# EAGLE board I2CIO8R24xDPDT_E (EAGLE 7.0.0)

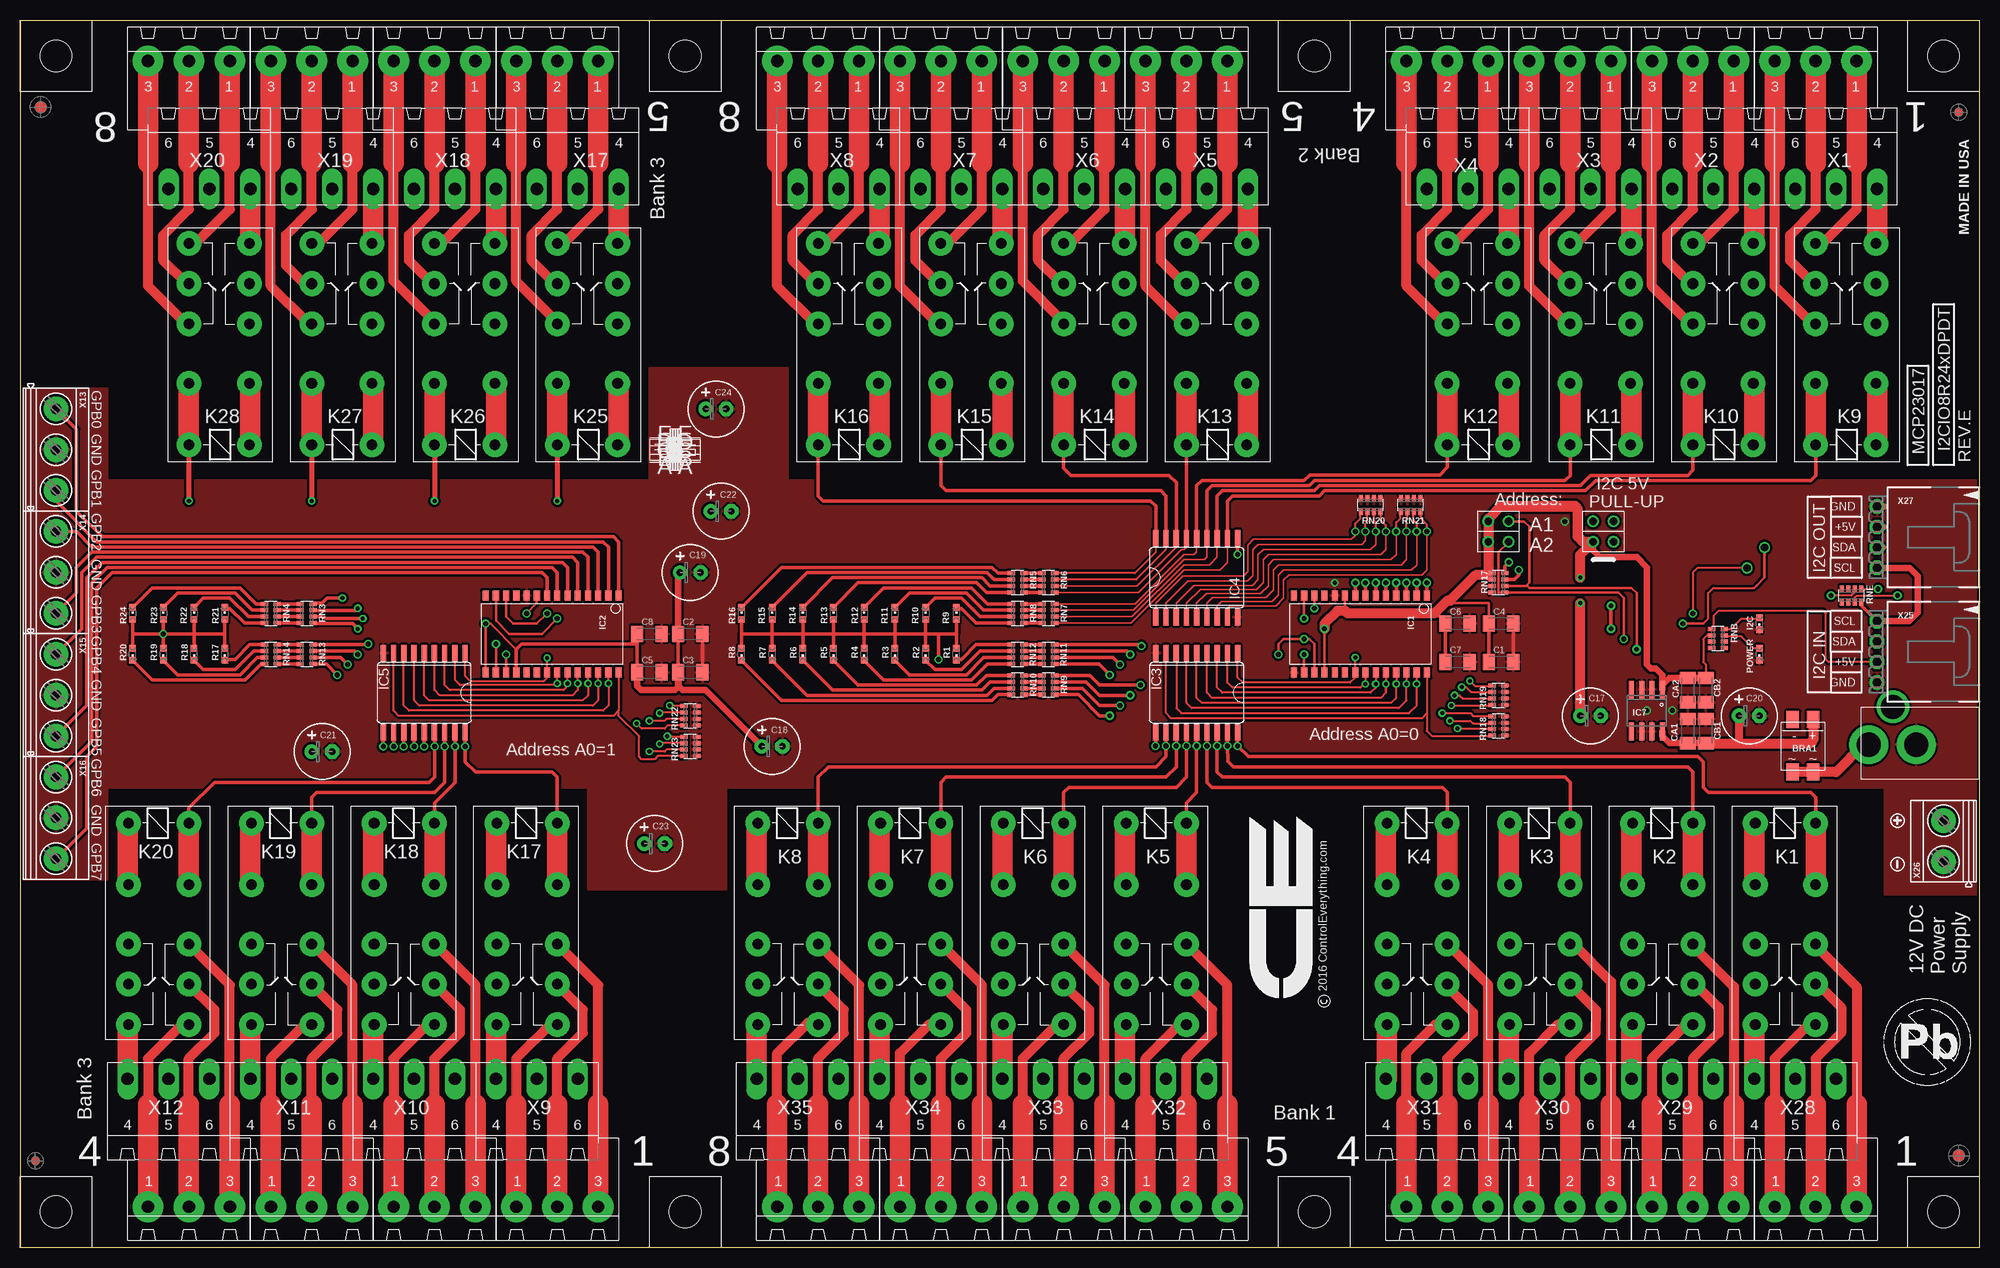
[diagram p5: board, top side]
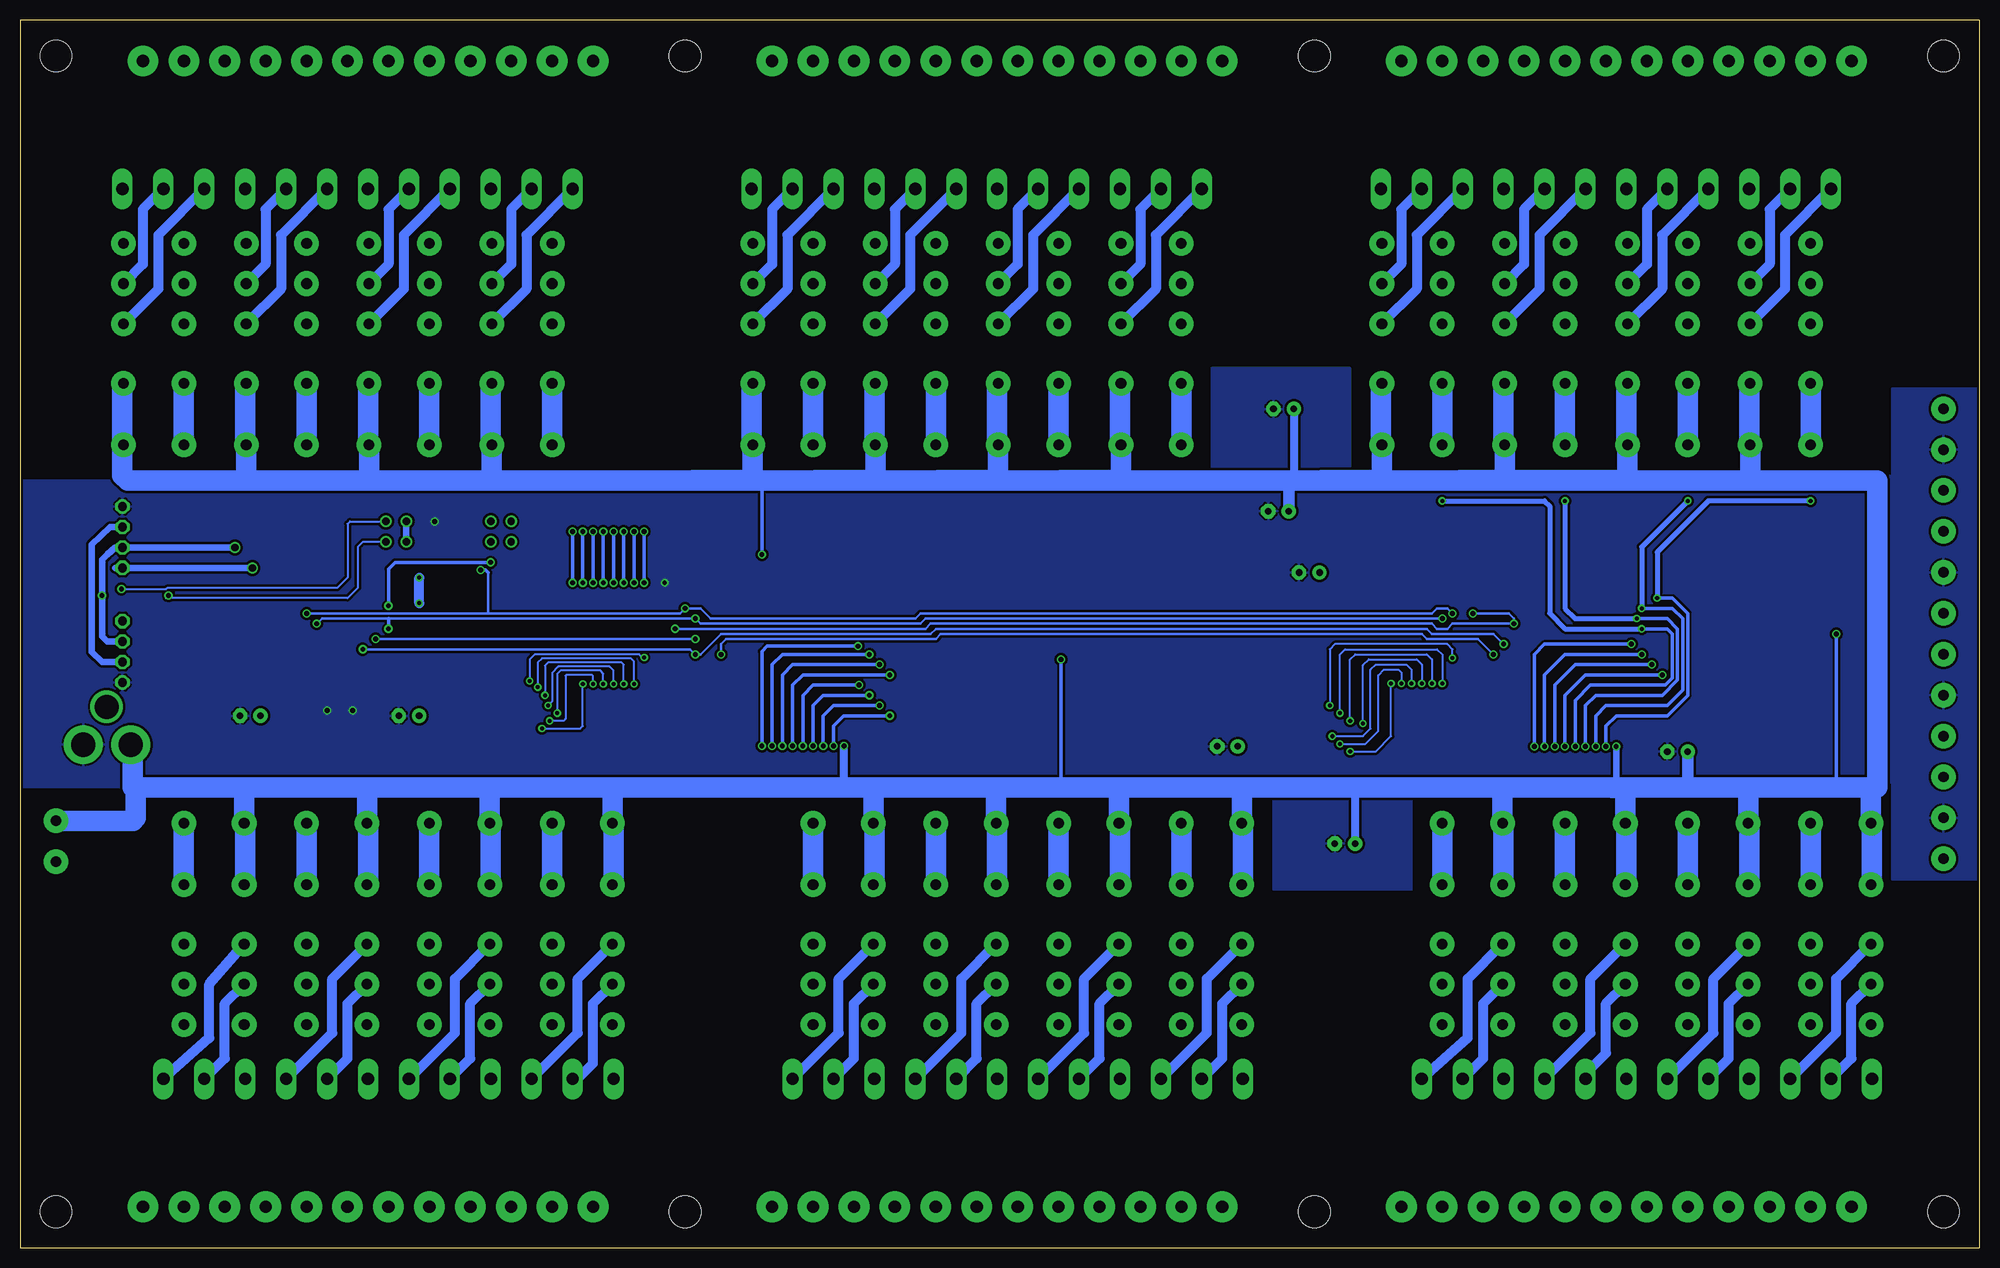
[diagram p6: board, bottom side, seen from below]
Size 243.2 x 152.41 mm. Coordinates in mm from the lower left corner, seen from the top.
Outline: 243.19,0 243.19,152.41 0,152.41 0,0.01 243.2,0.01
Copper layers (1*16): Top 0.035mm / dielectric 1.5mm / Bottom 0.035mm
Design rules "default": minimum track width 5mil, minimum drill 24mil, track to track 5mil, track to pad 5mil, pad to pad 5mil, via to via 5mil, smd to smd 5mil, copper to edge 10mil, drill to drill 8mil, minimum pad ring 10mil, minimum via ring 8mil, stop-mask expansion 2mil, vias tented up to drill 0mil, thermal gap 10mil

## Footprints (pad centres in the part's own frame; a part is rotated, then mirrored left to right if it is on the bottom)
MB2S = smd 1.55 x 2.1: + 0,-6.5; - 2.54,-6.5; ~@1 0,0; ~@2 2.54,0
_CA_.1UF_50V = smd 1.5 x 2: 1 -1.5,0; 2 1.5,0
_CB_10UF_25V = smd 1.5 x 2: 1 -1.5,0; 2 1.5,0
E-025X060 = drill 0.813 pad 1.778: + -1.27,0 | drill 0.813 pad 1.778 octagon: - 1.27,0
CC1206KRX7R9BB104 = smd 1.5 x 2: 1 -1.5,0; 2 1.5,0
TMK316F106ZL-T = smd 1.5 x 2: 1 -1.5,0; 2 1.5,0
CHIPLED_0603 = smd 0.8 x 0.8: A 0,-0.75; C 0,0.75
SO28W = smd 0.762 x 1.27: 1 -7.62,-4.78; 2 -6.35,-4.78; 3 -5.08,-4.78; 4 -3.81,-4.78; 5 -2.54,-4.78; 6 -1.27,-4.78; 7 0,-4.78; 8 1.27,-4.78; 9 2.54,-4.78; 10 3.81,-4.78; 11 5.08,-4.78; 12 6.35,-4.78; 13 7.62,-4.78; 14 8.89,-4.78; 15 8.89,4.78; 16 7.62,4.78; 17 6.35,4.78; 18 5.08,4.78; 19 3.81,4.78; 20 2.54,4.78; 21 1.27,4.78; 22 0,4.78; 23 -1.27,4.78; 24 -2.54,4.78; 25 -3.81,4.78; 26 -5.08,4.78; 27 -6.35,4.78; 28 -7.62,4.78
SO18L = smd 0.66 x 2.032: 1 -5.08,-4.902; 2 -3.81,-4.902; 3 -2.54,-4.902; 4 -1.27,-4.902; 5 0,-4.902; 6 1.27,-4.902; 7 2.54,-4.902; 8 3.81,-4.902; 9 5.08,-4.902; 10 5.08,4.902; 11 3.81,4.902; 12 2.54,4.902; 13 1.27,4.902; 14 0,4.902; 15 -1.27,4.902; 16 -2.54,4.902; 17 -3.81,4.902; 18 -5.08,4.902
_RGC_5V_SOIC8 = smd 0.6 x 2.2: 1 -1.905,-2.6; 2 -0.635,-2.6; 3 0.635,-2.6; 4 1.905,-2.6; 5 1.905,2.6; 6 0.635,2.6; 7 -0.635,2.6; 8 -1.905,2.6
G2R2 = drill 1.321 pad 3.048: 1 -2.54,-3.683; 2 -2.54,3.81; 3 5.08,-3.683; 4 5.08,3.81; O1 12.471,3.81; O2 12.471,-3.683; P1 17.45,3.81; P2 17.45,-3.683; S1 22.454,3.81; S2 22.454,-3.683
RNB = smd 0.5 x 0.9: 1 -1.2,-0.8; 2 -0.4,-0.8; 3 0.4,-0.8; 4 1.2,-0.8; 5 1.2,0.8; 6 0.4,0.8; 7 -0.4,0.8; 8 -1.2,0.8
RNE = smd 0.5 x 0.9: 1 -1.2,-0.8; 2 -0.4,-0.8; 3 0.4,-0.8; 4 1.2,-0.8; 5 1.2,0.8; 6 0.4,0.8; 7 -0.4,0.8; 8 -1.2,0.8
RND = smd 0.5 x 0.9: 1 -1.2,-0.8; 2 -0.4,-0.8; 3 0.4,-0.8; 4 1.2,-0.8; 5 1.2,0.8; 6 0.4,0.8; 7 -0.4,0.8; 8 -1.2,0.8
PCB_MOUNTING_HOLE = hole 3.962: 4.445,4.445
JUMPER_2X2 = drill 0.9: A1 0,2.54; A2 0,0; B1 2.54,2.54; B2 2.54,0
PJ-102A = drill 3 pad 4.8: RING 0.1,-3.39; TIP 0.1,-9.29 | drill 3 pad 3.251: RING_SW -4.6,-6.29
MDSTB3 = drill 1.524 pad 3.81: 1 -3.81,-10.795; 2 1.27,-10.795; 3 6.35,-10.795 | drill 1.524 pad 2.54 long: 4 -6.35,5.08; 5 -1.27,5.08; 6 3.81,5.08
MKDSN1,5/3-5,08 = drill 1.3 pad 3.048: 1 -7.641,0.025; 2 -2.561,0.025; 3 2.519,0.025
15-91-04 = drill 1.1 pad 1.778 octagon: 1 -3.81,-7.62; 2 -1.27,-7.62; 3 1.27,-7.62; 4 3.81,-7.62
MKDSN1,5/2-5,08 = drill 1.3 pad 3.048: 1 -2.561,0.025; 2 2.519,0.025

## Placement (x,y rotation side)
BRA1  MB2S_  [MB2S]  222.57,59.07 180 top
C1  [_CA_.1UF_50V]  183.83,72.72 0 top
C2  _CB_10UF_25VC1206K  [_CB_10UF_25V]  83.18,76.21 0 top
C3  [_CA_.1UF_50V]  83.18,71.45 0 top
C4  _CB_10UF_25VC1206K  [_CB_10UF_25V]  183.83,77.48 0 top
C5  [_CA_.1UF_50V]  78.11,71.45 0 top
C6  _CB_10UF_25VC1206K  [_CB_10UF_25V]  178.44,77.48 0 top
C7  [_CA_.1UF_50V]  178.44,72.72 0 top
C8  _CB_10UF_25VC1206K  [_CB_10UF_25V]  78.11,76.21 0 top
C17  100uF  [E-025X060]  194.94,66.05 0 top
C18  100uF  [E-025X060]  93.34,62.24 0 top
C19  100uF  [E-025X060]  83.18,83.83 0 top
C20  100uF  [E-025X060]  214.63,66.05 0 top
C21  100uF  [E-025X060]  37.46,61.61 0 top
C22  100uF  [E-025X060]  86.99,91.45 0 top
C23  100uF  [E-025X060]  78.74,50.18 0 top
C24  100uF  [E-025X060]  86.36,104.15 0 top
CA1  [CC1206KRX7R9BB104]  207.01,64.15 270 top
CA2  [CC1206KRX7R9BB104]  207.01,69.23 90 top
CB1  [TMK316F106ZL-T]  209.23,64.15 270 top
CB2  [TMK316F106ZL-T]  209.23,69.23 90 top
I2C  LED_NCD  [CHIPLED_0603]  215.9,77.48 180 top
IC1  MCP23017SO  [SO28W]  167,76.21 180 top
IC2  MCP23017SO  [SO28W]  66.67,76.21 180 top
IC3  ULN2803  [SO18L]  146.05,68.91 180 top
IC4  ULN2803  [SO18L]  146.05,83.2 0 top
IC5  ULN2803  [SO18L]  50.17,68.91 180 top
IC7  _RGC_5V_SOIC805  [_RGC_5V_SOIC8]  201.93,66.69 180 top
K1  G2R2  [G2R2]  219.07,50.18 270 top
K2  G2R2  [G2R2]  203.83,50.18 270 top
K3  G2R2  [G2R2]  188.59,50.18 270 top
K4  G2R2  [G2R2]  173.36,50.18 270 top
K5  G2R2  [G2R2]  140.97,50.18 270 top
K6  G2R2  [G2R2]  125.73,50.18 270 top
K7  G2R2  [G2R2]  110.49,50.18 270 top
K8  G2R2  [G2R2]  95.25,50.18 270 top
K9  G2R2  [G2R2]  226.69,102.25 90 top
K10  G2R2  [G2R2]  211.45,102.25 90 top
K11  G2R2  [G2R2]  196.21,102.25 90 top
K12  G2R2  [G2R2]  180.97,102.25 90 top
K13  G2R2  [G2R2]  148.59,102.25 90 top
K14  G2R2  [G2R2]  133.35,102.25 90 top
K15  G2R2  [G2R2]  118.11,102.25 90 top
K16  G2R2  [G2R2]  102.87,102.25 90 top
K17  G2R2  [G2R2]  62.86,50.18 270 top
K18  G2R2  [G2R2]  47.62,50.18 270 top
K19  G2R2  [G2R2]  32.38,50.18 270 top
K20  G2R2  [G2R2]  17.14,50.18 270 top
K25  G2R2  [G2R2]  70.48,102.25 90 top
K26  G2R2  [G2R2]  55.24,102.25 90 top
K27  G2R2  [G2R2]  40,102.25 90 top
K28  G2R2  [G2R2]  24.77,102.25 90 top
POWER  LED_NCD  [CHIPLED_0603]  215.9,73.67 180 top
R1  LED_NCD  [CHIPLED_0603]  116.2,73.67 180 top
R2  LED_NCD  [CHIPLED_0603]  112.39,73.67 180 top
R3  LED_NCD  [CHIPLED_0603]  108.58,73.67 180 top
R4  LED_NCD  [CHIPLED_0603]  104.77,73.67 180 top
R5  LED_NCD  [CHIPLED_0603]  100.96,73.67 180 top
R6  LED_NCD  [CHIPLED_0603]  97.15,73.67 180 top
R7  LED_NCD  [CHIPLED_0603]  93.34,73.67 180 top
R8  LED_NCD  [CHIPLED_0603]  89.53,73.67 180 top
R9  LED_NCD  [CHIPLED_0603]  116.2,78.75 0 top
R10  LED_NCD  [CHIPLED_0603]  112.39,78.75 0 top
R11  LED_NCD  [CHIPLED_0603]  108.58,78.75 0 top
R12  LED_NCD  [CHIPLED_0603]  104.77,78.75 0 top
R13  LED_NCD  [CHIPLED_0603]  100.96,78.75 0 top
R14  LED_NCD  [CHIPLED_0603]  97.15,78.75 0 top
R15  LED_NCD  [CHIPLED_0603]  93.34,78.75 0 top
R16  LED_NCD  [CHIPLED_0603]  89.53,78.75 0 top
R17  LED_NCD  [CHIPLED_0603]  25.4,73.67 180 top
R18  LED_NCD  [CHIPLED_0603]  21.59,73.67 180 top
R19  LED_NCD  [CHIPLED_0603]  17.78,73.67 180 top
R20  LED_NCD  [CHIPLED_0603]  13.97,73.67 180 top
R21  LED_NCD  [CHIPLED_0603]  25.4,78.75 0 top
R22  LED_NCD  [CHIPLED_0603]  21.59,78.75 0 top
R23  LED_NCD  [CHIPLED_0603]  17.78,78.75 0 top
R24  LED_NCD  [CHIPLED_0603]  13.97,78.75 0 top
RN3  _RNB_510  [RNB]  35.56,78.75 270 top
RN4  _RNB_510  [RNB]  31.11,78.75 270 top
RN5  _RNB_510  [RNB]  123.83,82.56 270 top
RN6  _RNB_510  [RNB]  127.64,82.56 270 top
RN7  _RNB_510  [RNB]  127.64,78.75 270 top
RN8  _RNB_510  [RNB]  123.83,78.75 270 top
RN9  _RNB_510  [RNB]  127.64,69.86 270 top
RN10  _RNB_510  [RNB]  123.83,69.86 270 top
RN11  _RNB_510  [RNB]  127.64,73.67 90 top
RN12  _RNB_510  [RNB]  123.83,73.67 90 top
RN13  _RNB_510  [RNB]  35.56,73.67 270 top
RN14  _RNB_510  [RNB]  31.11,73.67 270 top
RN17  _RNE_10K  [RNE]  183.51,82.56 270 top
RN18  _RNE_10K  [RNE]  183.51,64.78 90 top
RN19  _RNE_10K  [RNE]  183.51,68.59 90 top
RN20  _RNE_10K  [RNE]  167.64,92.21 180 top
RN21  _RNE_10K  [RNE]  172.59,92.21 180 top
RN22  _RNE_10K  [RNE]  83.18,66.05 90 top
RN23  _RNE_10K  [RNE]  83.18,62.24 90 top
RNB  _RNB_510  [RNB]  210.76,75.64 90 top
RNE  _RND_4.7K  [RND]  227.33,80.98 0 top
U$1  PCB_MOUNTING_HOLE  [PCB_MOUNTING_HOLE]  165.1,143.52 90 top
U$3  NOPB_LOGO_SYM  [NOPB_LOGO_SYM]  231.14,19.7 0 top
U$4  PCB_MOUNTING_HOLE  [PCB_MOUNTING_HOLE]  0,8.9 270 top
U$5  PCB_MOUNTING_HOLE  [PCB_MOUNTING_HOLE]  243.2,143.52 90 top
U$7  PCB_MOUNTING_HOLE  [PCB_MOUNTING_HOLE]  8.89,143.52 90 top
U$9  PCB_MOUNTING_HOLE  [PCB_MOUNTING_HOLE]  86.99,143.52 90 top
U$10  PCB_MOUNTING_HOLE  [PCB_MOUNTING_HOLE]  156.21,8.9 270 top
U$11  PCB_MOUNTING_HOLE  [PCB_MOUNTING_HOLE]  234.31,8.9 270 top
U$12  PCB_MOUNTING_HOLE  [PCB_MOUNTING_HOLE]  78.11,8.9 270 top
U$13  JUMPER_2X2  [JUMPER_2X2]  182.25,90.18 270 top
U$14  2.1MMJACK  [PJ-102A]  238.76,62.56 270 top
U$15  [VISION_REF15]  240.66,11.44 90 top
U$16  JUMPER_2X2  [JUMPER_2X2]  195.26,90.18 270 top
U$18  [VISION_REF10]  240.66,140.98 90 top
U$21  [ICON_USA]  241.94,125.74 90 top
U$22  [ICON_MINUS]  233.04,47.64 90 top
U$23  [VISION_REF15]  2.54,141.62 90 top
U$24  [ICON_PLUS]  233.04,53.04 0 top
U$28  [VISION_REF10]  1.91,10.81 90 top
X1  MDSTB3  [MDSTB3]  224.15,136.54 180 top
X2  MDSTB3  [MDSTB3]  208.91,136.54 180 top
X3  MDSTB3  [MDSTB3]  193.67,136.54 180 top
X4  MDSTB3  [MDSTB3]  178.44,136.54 180 top
X5  MDSTB3  [MDSTB3]  146.05,136.54 180 top
X6  MDSTB3  [MDSTB3]  130.81,136.54 180 top
X7  MDSTB3  [MDSTB3]  115.57,136.54 180 top
X8  MDSTB3  [MDSTB3]  100.33,136.54 180 top
X9  MDSTB3  [MDSTB3]  65.4,15.89 0 top
X10  MDSTB3  [MDSTB3]  50.17,15.89 0 top
X11  MDSTB3  [MDSTB3]  34.92,15.89 0 top
X12  MDSTB3  [MDSTB3]  19.69,15.89 0 top
X13  MKDSN1,5/3-5,08  [MKDSN1,5/3-5,08]  4.44,96.53 270 top
X14  MKDSN1,5/3-5,08  [MKDSN1,5/3-5,08]  4.44,81.29 270 top
X15  MKDSN1,5/3-5,08  [MKDSN1,5/3-5,08]  4.44,66.05 270 top
X16  MKDSN1,5/3-5,08  [MKDSN1,5/3-5,08]  4.44,50.81 270 top
X17  MDSTB3  [MDSTB3]  67.95,136.54 180 top
X18  MDSTB3  [MDSTB3]  52.7,136.54 180 top
X19  MDSTB3  [MDSTB3]  37.46,136.54 180 top
X20  MDSTB3  [MDSTB3]  22.22,136.54 180 top
X25  C-GRID-04-15-91-3044  [15-91-04]  238.12,73.99 270 top
X26  MKDSN1,5/2-5,08  [MKDSN1,5/2-5,08]  238.76,50.5 90 top
X27  C-GRID-04-15-91-3044  [15-91-04]  238.12,88.21 270 top
X28  MDSTB3  [MDSTB3]  221.62,15.89 0 top
X29  MDSTB3  [MDSTB3]  206.38,15.89 0 top
X30  MDSTB3  [MDSTB3]  191.13,15.89 0 top
X31  MDSTB3  [MDSTB3]  175.89,15.89 0 top
X32  MDSTB3  [MDSTB3]  143.51,15.89 0 top
X33  MDSTB3  [MDSTB3]  128.27,15.89 0 top
X34  MDSTB3  [MDSTB3]  113.03,15.89 0 top
X35  MDSTB3  [MDSTB3]  97.79,15.89 0 top

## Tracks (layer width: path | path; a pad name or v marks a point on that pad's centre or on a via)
GND  (via drill 0.5, 0.6)
  Top 0.406: C1.2 C4.2 | C3.2 C2.2 | 231.14,70.18 X25.4
  Top 0.813: X27.1 231.39,92.02
  other vias: 205.1,66.69 201.93,66.69 191.77,90.18 163.19,82.56
  pour Top (isolate 0.305): 243.14,43.83 231.46,43.83 231.46,57.16 243.14,57.16
  pour Top (isolate 0.305): 0,95.26 243.2,95.26 243.2,57.16 0,57.16
  pour Bottom (isolate 0.305): 0,57.8 0,95.9 243.2,95.26 243.2,57.16
  pour Bottom (isolate 0.305): 10.8,45.73 0,45.73 0,106.69 10.8,106.69
  pour Top (isolate 0.305): 10.8,45.73 0,45.73 0,106.69 10.8,106.69
  pour Top (isolate 0.305): 70.48,57.8 70.48,44.46 87.63,44.46 87.63,57.16 73.02,57.16 73.02,57.8
  pour Bottom (isolate 0.305): 70.48,44.46 70.48,57.8 87.63,57.8 87.63,44.46
  pour Bottom (isolate 0.305): 78.11,93.99 78.11,109.23 95.25,109.23 95.25,93.99
  pour Top (isolate 0.305): 78.11,94.63 78.11,109.23 95.25,109.23 95.25,94.63
GPB0
  Top 0.406: IC2.1 74.3,87.64 73.66,88.28 10.16,88.28 6.98,91.45 6.98,101.66 X13.1
GPB1
  Top 0.406: X13.3 4.42,92.74 9.52,87.64 72.39,87.64 73.02,87.01 IC2.2
GPB2
  Top 0.406: X14.1 7.01,88.93 8.89,87.01 71.12,87.01 71.76,86.37 IC2.3
GPB3
  Top 0.406: X14.3 6.98,81.29 6.98,84.47 8.89,86.37 69.85,86.37 70.48,85.74 IC2.4
GPB4
  Top 0.406: X15.1 7.62,76.85 7.62,83.83 9.52,85.74 68.58,85.74 69.21,85.1 IC2.5
GPB5
  Top 0.406: X15.3 8.25,67.32 8.25,83.2 10.16,85.1 67.31,85.1 67.95,84.47 IC2.6
GPB6
  Top 0.406: X16.1 8.89,62.88 8.89,82.56 10.8,84.47 66.04,84.47 66.67,83.83 IC2.7
GPB7
  Top 0.406: X16.3 8.25,52.08 8.25,60.97 9.52,62.24 9.52,81.93 11.43,83.83 64.77,83.83 65.4,83.2 IC2.8
I2C_SCL  (via drill 0.6, 0.9)
  Top 0.254: v214.38,84.4 208.22,84.4 207.64,83.83 v207.64,78.75
  Top 0.305: IC2.12 60.33,78.38 61.22,77.48 64.14,77.48 v65.4,78.75 | v160.65,79.39 IC1.12
  Top 0.406: RN17.7 185.5,82.96 186.06,83.51 v186.06,84.15 | RNE.4 228.53,79.76 X25.1
  Top 0.813: X25.1 234.53,77.8 235.58,78.86 235.58,83.37 234.55,84.4 X27.4
  Bottom 0.305: v207.64,78.75 185.1,78.75 | 185.1,78.75 161.29,78.75 v160.65,79.39 158.75,79.39 157.48,78.12 132.08,78.12 131.44,78.75 67.95,78.75 67.31,79.39 66.04,79.39 v65.4,78.75 | 185.1,83.83 185.1,78.75
  Bottom 0.406: v186.06,84.15 185.42,84.15 185.1,83.83
  Bottom 0.813: v214.38,84.4 X27.4 231.39,84.4
I2C_SDA  (via drill 0.6, 0.9)
  Top 0.254: RNE.3 227.73,80.74 227.96,80.98 v233.04,80.98 | 208.91,77.48 209.55,78.12 209.55,81.29 210.19,81.93 215.26,81.93 215.58,82.25
  Top 0.305: IC2.13 59.05,77.87 60.71,76.21 64.77,76.21 v66.67,78.12 | v159.38,78.12 IC1.13 | v216.53,86.94 216.53,83.2 215.58,82.25 | 208.91,77.48 v206.38,77.48
  Top 0.406: RN17.8 184.31,84.63 v184.78,85.1 | v197.48,79.7 v197.48,76.85
  Top 0.61: X27.3 231.39,86.94 | X25.2 231.14,75.26
  Bottom 0.305: v66.67,78.12 130.81,78.12 131.44,77.48 158.75,77.48 v159.38,78.12 197.48,78.12 205.74,78.12 v206.38,77.48
  Bottom 0.406: v184.78,85.1 196.67,85.1 197.48,84.29 v197.48,79.7 | v197.48,76.85 197.48,78.12 | 231.14,75.26 X25.2
  Bottom 0.813: 231.14,75.26 232.41,75.26 233.04,75.89 v233.04,80.98 233.04,85.42 232.41,86.06 231.39,86.94 X27.3 v216.53,86.94
N$1
  Bottom 1.27: X1.5 227.96,128.92 227.96,122.11 K9.P2
N$2
  Bottom 1.27: X1.6 226.06,125.74 226.06,119.04 K9.O2
N$3
  Top 2.54: X1.4 230.5,124.83 K9.S2
N$4
  Top 1.27: K9.P1 222.58,119.7 219.71,122.57 219.71,125.74 222.88,128.92 222.88,134.63
  Top 2.54: X1.2 222.88,134.63
N$5
  Top 1.27: K9.O1 222.48,114.72 217.81,119.39 217.81,134.63
  Top 2.54: X1.3 217.81,134.63
N$6
  Top 1.27: K9.S1 223.75,124.7 227.96,128.92 227.96,134.63
  Top 2.54: X1.1 227.96,134.63
N$7
  Bottom 1.27: X2.5 212.72,128.92 212.72,122.11 K10.P2
N$8
  Bottom 1.27: X2.6 210.82,125.74 210.82,119.04 K10.O2
N$9
  Top 2.54: X2.4 215.26,124.83 K10.S2
N$10
  Top 1.27: K10.S1 208.51,124.7 212.72,128.92 212.72,134.63
  Top 2.54: X2.1 212.72,134.63
N$11
  Top 1.27: K10.P1 207.34,119.7 204.47,122.57 204.47,125.74 207.64,128.92 207.64,134.63
  Top 2.54: X2.2 207.64,134.63
N$12
  Top 1.27: K10.O1 207.24,114.72 202.56,119.39 202.56,134.63
  Top 2.54: X2.3 202.56,134.63
N$13
  Bottom 1.27: X3.5 197.48,128.92 197.48,122.11 K11.P2
N$14
  Bottom 1.27: X3.6 195.58,125.74 195.58,119.04 K11.O2
N$15
  Bottom 1.27: X4.5 182.25,128.92 182.25,122.11 K12.P2
N$16
  Bottom 1.27: X4.6 180.34,125.74 180.34,119.04 K12.O2
N$17
  Top 2.54: X3.4 200.02,124.83 K11.S2
N$18
  Top 2.54: X4.4 184.78,124.83 K12.S2
N$19
  Top 1.27: K11.O1 192,114.72 187.32,119.39 187.32,134.63
  Top 2.54: X3.3 187.32,134.63
N$20
  Top 1.27: K12.O1 176.76,114.72 172.08,119.39 172.08,134.63
  Top 2.54: X4.3 172.08,134.63
N$21
  Top 1.27: K12.P1 176.86,119.7 173.99,122.57 173.99,125.74 177.17,128.92 177.17,134.63
  Top 2.54: X4.2 177.17,134.63
N$22
  Top 1.27: K11.P1 192.1,119.7 189.23,122.57 189.23,125.74 192.4,128.92 192.4,134.63
  Top 2.54: X3.2 192.4,134.63
N$23
  Top 1.27: K11.S1 193.27,124.7 197.48,128.92 197.48,134.63
  Top 2.54: X3.1 197.48,134.63
N$24
  Top 1.27: K12.S1 178.03,124.7 182.25,128.92 182.25,134.63
  Top 2.54: X4.1 182.25,134.63
N$25
  Bottom 1.27: X5.6 147.95,125.74 147.95,119.04 K13.O2
N$26
  Bottom 1.27: X5.5 149.86,128.92 149.86,122.11 K13.P2
N$27
  Top 2.54: X5.4 152.4,124.83 K13.S2
N$28
  Top 1.27: K13.P1 144.48,119.7 141.61,122.57 141.61,125.74 144.78,128.92 144.78,134.63
  Top 2.54: X5.2 144.78,134.63
N$29
  Top 1.27: K13.S1 145.64,124.7 149.86,128.92 149.86,134.63
  Top 2.54: X5.1 149.86,134.63
N$30
  Top 1.27: K13.O1 144.37,114.72 139.7,119.39 139.7,134.63
  Top 2.54: X5.3 139.7,134.63
N$31
  Bottom 1.27: X6.5 134.62,128.92 134.62,122.11 K14.P2
N$32
  Bottom 1.27: X6.6 132.71,125.74 132.71,119.04 K14.O2
N$33
  Top 1.27: K14.P1 129.24,119.7 126.36,122.57 126.36,125.74 129.54,128.92 129.54,134.63
  Top 2.54: X6.2 129.54,134.63
N$34
  Top 1.27: K14.S1 130.4,124.7 134.62,128.92 134.62,134.63
  Top 2.54: X6.1 134.62,134.63
N$35
  Top 1.27: K15.P1 113.99,119.7 111.12,122.57 111.12,125.74 114.3,128.92 114.3,134.63
  Top 2.54: X7.2 114.3,134.63
N$36
  Top 1.27: K16.P1 98.76,119.7 95.89,122.57 95.89,125.74 99.06,128.92 99.06,134.63
  Top 2.54: X8.2 99.06,134.63
N$37
  Bottom 1.27: X8.5 104.14,128.92 104.14,122.11 K16.P2
N$38
  Bottom 1.27: X8.6 102.23,125.74 102.23,119.04 K16.O2
N$39
  Top 1.27: K14.O1 129.54,114.95 124.46,120.03 124.46,134.63
  Top 2.54: X6.3 124.46,134.63
N$40
  Top 1.27: K16.O1 98.65,114.72 93.98,119.39 93.98,134.63
  Top 2.54: X8.3 93.98,134.63
N$41
  Top 1.27: K15.O1 113.89,114.72 109.22,119.39 109.22,134.63
  Top 2.54: X7.3 109.22,134.63
N$42
  Bottom 1.27: X7.6 117.48,125.74 117.48,119.04 K15.O2
N$43
  Bottom 1.27: X7.5 119.38,128.92 119.38,122.11 K15.P2
N$44
  Top 2.54: X6.4 137.16,124.83 K14.S2
N$45
  Top 2.54: X7.4 121.92,124.83 K15.S2
N$46
  Top 1.27: K15.S1 115.16,124.7 119.38,128.92 119.38,134.63
  Top 2.54: X7.1 119.38,134.63
N$47
  Top 1.27: K16.S1 99.92,124.7 104.14,128.92 104.14,134.63
  Top 2.54: X8.1 104.14,134.63
N$48
  Top 2.54: X8.4 106.68,124.83 K16.S2
N$49
  Bottom 1.27: X9.5 61.59,23.51 61.59,30.31 K17.P2
N$50
  Bottom 1.27: X9.6 63.5,26.05 63.5,33.39 K17.O2
N$51
  Top 2.54: X9.4 59.05,27.6 K17.S2
N$52
  Top 1.27: 66.67,17.79 66.67,23.51 69.85,26.68 69.85,29.55 K17.P1
  Top 2.54: X9.2 66.67,17.79
N$53
  Top 1.27: 71.76,17.79 71.76,32.63 K17.O1
  Top 2.54: X9.3 71.76,17.79
N$54
  Top 1.27: K17.S1 66.04,27.95 61.59,23.51 61.59,17.79
  Top 2.54: X9.1 61.59,17.79
N$55
  Bottom 1.27: X10.5 48.89,21.6 46.35,24.14 46.35,30.31 K18.P2
N$56
  Bottom 1.27: X10.6 48.26,26.68 48.26,33.39 K18.O2
N$57
  Top 2.54: X10.4 43.81,27.6 K18.S2
N$58
  Top 1.27: K18.S1 50.57,27.72 46.35,23.51 46.35,17.79
  Top 2.54: X10.1 46.35,17.79
N$59
  Top 1.27: 51.43,17.79 51.43,23.51 54.61,26.68 54.61,29.55 K18.P1
  Top 2.54: X10.2 51.43,17.79
N$60
  Top 1.27: 56.52,17.79 56.52,32.63 K18.O1
  Top 2.54: X10.3 56.52,17.79
N$61
  Bottom 1.27: X11.5 31.11,23.51 31.11,30.31 K19.P2
N$62
  Bottom 1.27: X11.6 33.02,26.68 33.02,33.39 K19.O2
N$63
  Bottom 1.27: X12.5 15.88,23.51 15.88,30.31 K20.P2
N$64
  Bottom 1.27: X12.6 17.78,26.68 17.78,33.39 K20.O2
N$65
  Top 2.54: X11.4 28.58,27.6 K19.S2
N$66
  Top 2.54: X12.4 13.33,27.6 K20.S2
N$67
  Top 1.27: 41.27,17.79 41.27,32.63 K19.O1
  Top 2.54: X11.3 41.27,17.79
N$68
  Top 1.27: 26.03,17.79 26.03,32.63 K20.O1
  Top 2.54: X12.3 26.03,17.79
N$69
  Top 1.27: 20.95,17.79 20.95,23.51 24.13,26.68 24.13,29.55 K20.P1
  Top 2.54: X12.2 20.95,17.79
N$70
  Top 1.27: 36.19,17.79 36.19,23.51 39.37,26.68 39.37,29.55 K19.P1
  Top 2.54: X11.2 36.19,17.79
N$71
  Top 1.27: K19.S1 35.33,27.72 31.11,23.51 31.11,17.79
  Top 2.54: X11.1 31.11,17.79
N$72
  Top 1.27: K20.S1 20.32,27.95 15.88,23.51 15.88,17.79
  Top 2.54: X12.1 15.88,17.79
N$97
  Bottom 1.27: X17.5 71.76,128.92 71.76,122.11 K25.P2
N$98
  Bottom 1.27: X17.6 69.85,125.74 69.85,119.04 K25.O2
N$99
  Top 2.54: X17.4 74.3,124.83 K25.S2
N$100
  Top 1.27: K25.P1 66.37,119.7 63.5,122.57 63.5,125.74 66.67,128.92 66.67,134.63
  Top 2.54: X17.2 66.67,134.63
N$101
  Top 1.27: K25.O1 66.67,114.95 61.59,120.03 61.59,134.63
  Top 2.54: X17.3 61.59,134.63
N$102
  Top 1.27: K25.S1 67.54,124.7 71.76,128.92 71.76,134.63
  Top 2.54: X17.1 71.76,134.63
N$103
  Bottom 1.27: X18.5 56.52,128.92 56.52,122.11 K26.P2
N$104
  Bottom 1.27: X18.6 54.61,125.74 54.61,119.04 K26.O2
N$105
  Top 2.54: X18.4 59.05,124.83 K26.S2
N$106
  Top 1.27: K26.S1 52.3,124.7 56.52,128.92 56.52,134.63
  Top 2.54: X18.1 56.52,134.63
N$107
  Top 1.27: K26.P1 51.13,119.7 48.26,122.57 48.26,125.74 51.43,128.92 51.43,134.63
  Top 2.54: X18.2 51.43,134.63
N$108
  Top 1.27: K26.O1 51.43,114.95 46.35,120.03 46.35,134.63
  Top 2.54: X18.3 46.35,134.63
N$109
  Bottom 1.27: X19.5 41.27,128.92 41.27,122.11 K27.P2
N$110
  Bottom 1.27: X19.6 39.37,125.74 39.37,119.04 K27.O2
N$111
  Bottom 1.27: X20.5 26.03,128.92 26.03,122.11 K28.P2
N$112
  Bottom 1.27: X20.6 24.13,125.74 24.13,119.04 K28.O2
N$113
  Top 2.54: X19.4 43.81,124.83 K27.S2
N$114
  Top 2.54: X20.4 28.58,124.83 K28.S2
N$115
  Top 1.27: K27.O1 35.79,114.72 31.11,119.39 31.11,134.63
  Top 2.54: X19.3 31.11,134.63
N$116
  Top 1.27: K28.O1 20.55,114.72 15.88,119.39 15.88,134.63
  Top 2.54: X20.3 15.88,134.63
N$117
  Top 1.27: K28.P1 20.65,119.7 17.78,122.57 17.78,125.74 20.95,128.92 20.95,134.63
  Top 2.54: X20.2 20.95,134.63
N$118
  Top 1.27: K27.P1 35.25,119.7 33.02,121.93 33.02,125.74 36.19,128.92 36.19,134.63
  Top 2.54: X19.2 36.19,134.63
N$119
  Top 1.27: K27.S1 37.06,124.7 41.27,128.92 41.27,134.63
  Top 2.54: X19.1 41.27,134.63
N$120
  Top 1.27: K28.S1 21.82,124.7 26.03,128.92 26.03,134.63
  Top 2.54: X20.1 26.03,134.63
N$203
  Bottom 1.27: X28.5 217.81,23.51 217.81,30.31 K1.P2
N$204
  Bottom 1.27: X28.6 219.71,26.05 219.71,32.75 K1.O2
N$205
  Top 2.54: X28.4 215.26,27.6 K1.S2
N$206
  Top 1.27: K1.P1 223.19,32.73 226.06,29.86 226.06,26.68 222.88,23.51 222.88,17.79
  Top 2.54: X28.2 222.88,17.79
N$207
  Top 1.27: K1.O1 222.88,37.48 227.96,32.4 227.96,17.79
  Top 2.54: X28.3 227.96,17.79
N$208
  Top 1.27: K1.S1 222.02,27.72 217.81,23.51 217.81,17.79
  Top 2.54: X28.1 217.81,17.79
N$209
  Bottom 1.27: X29.5 202.56,23.51 202.56,30.31 K2.P2
N$210
  Bottom 1.27: X29.6 204.47,26.68 204.47,33.39 K2.O2
N$211
  Top 2.54: X29.4 200.02,27.6 K2.S2
N$212
  Top 1.27: K2.S1 206.38,27.32 202.56,23.51 202.56,17.79
  Top 2.54: X29.1 202.56,17.79
N$213
  Top 1.27: K2.P1 207.95,32.73 210.82,29.86 210.82,26.68 207.64,23.51 207.64,17.79
  Top 2.54: X29.2 207.64,17.79
N$214
  Top 1.27: K2.O1 207.64,37.48 212.72,32.4 212.72,17.79
  Top 2.54: X29.3 212.72,17.79
N$215
  Bottom 1.27: X30.5 187.32,23.51 187.32,30.31 K3.P2
N$216
  Bottom 1.27: X30.6 189.23,26.68 189.23,33.39 K3.O2
N$217
  Bottom 1.27: X31.5 173.99,20.97 172.08,22.87 172.08,30.31 K4.P2
N$218
  Bottom 1.27: X31.6 173.99,26.68 173.99,33.39 K4.O2
N$219
  Top 2.54: X30.4 184.78,27.6 K3.S2
N$220
  Top 2.54: X31.4 169.67,20.97 K4.S2
N$221
  Top 1.27: K3.O1 192.81,37.71 197.48,33.03 197.48,17.79
  Top 2.54: X30.3 197.48,17.79
N$222
  Top 1.27: 182.25,17.79 182.25,32.63 K4.O1
  Top 2.54: X31.3 182.25,17.79
N$223
  Top 1.27: K4.P1 177.17,32.4 180.34,29.22 180.34,26.68 177.17,23.51 177.17,17.79
  Top 2.54: 177.17,17.79 X31.2
N$224
  Top 1.27: 192.4,17.79 192.4,23.51 195.58,26.68 195.63,29.48 195.27,29.86 K3.P1
  Top 2.54: X30.2 192.4,17.79
N$225
  Top 1.27: 187.32,17.79 187.32,24.14 190.91,27.72 K3.S1
  Top 2.54: X30.1 187.32,17.79
N$226
  Top 1.27: 172.08,17.79 172.08,24.14 175.67,27.72 K4.S1
  Top 2.54: X31.1 172.08,17.79
N$304
  Bottom 1.27: X32.6 141.61,26.68 141.61,33.39 K5.O2
N$305
  Bottom 1.27: X32.5 139.7,23.51 139.7,30.31 K5.P2
N$306
  Top 2.54: X32.4 137.16,27.6 K5.S2
N$307
  Top 1.27: 144.78,17.79 144.78,23.51 147.95,26.68 147.95,29.55 K5.P1
  Top 2.54: X32.2 144.78,17.79
N$308
  Top 1.27: 139.7,17.79 139.7,23.51 143.92,27.72 K5.S1
  Top 2.54: X32.1 139.7,17.79
N$309
  Top 1.27: 149.86,17.79 149.86,32.63 K5.O1
  Top 2.54: X32.3 149.86,17.79
N$310
  Bottom 1.27: X33.5 124.46,23.51 124.46,30.31 K6.P2
N$311
  Bottom 1.27: X33.6 126.36,26.68 126.36,33.39 K6.O2
N$312
  Top 1.27: 129.54,17.79 129.54,23.51 132.71,26.68 132.71,29.55 K6.P1
  Top 2.54: X33.2 129.54,17.79
N$313
  Top 1.27: 124.46,17.79 124.46,23.51 128.68,27.72 K6.S1
  Top 2.54: X33.1 124.46,17.79
N$314
  Top 1.27: 114.3,17.79 114.3,23.51 117.48,26.68 117.48,29.55 K7.P1
  Top 2.54: X34.2 114.3,17.79
N$315
  Top 1.27: 99.06,17.79 99.06,23.51 102.23,26.68 102.23,29.55 K8.P1
  Top 2.54: X35.2 99.06,17.79
N$316
  Bottom 1.27: X35.5 93.98,23.51 93.98,30.31 K8.P2
N$317
  Bottom 1.27: X35.6 95.89,26.68 95.89,33.39 K8.O2
N$318
  Top 1.27: 134.62,17.79 134.62,32.63 K6.O1
  Top 2.54: X33.3 134.62,17.79
N$319
  Top 1.27: 104.14,17.79 104.14,32.63 K8.O1
  Top 2.54: X35.3 104.14,17.79
N$320
  Top 1.27: 119.38,17.79 119.38,32.63 K7.O1
  Top 2.54: X34.3 119.38,17.79
N$321
  Bottom 1.27: X34.6 111.12,26.68 111.12,33.39 K7.O2
N$322
  Bottom 1.27: X34.5 109.22,23.51 109.22,30.31 K7.P2
N$323
  Top 2.54: X33.4 121.92,27.6 K6.S2
N$324
  Top 2.54: X34.4 106.68,27.6 K7.S2
N$325
  Top 1.27: 109.22,17.79 109.22,24.14 112.8,27.72 K7.S1
  Top 2.54: X34.1 109.22,17.79
N$326
  Top 1.27: 93.98,17.79 93.98,24.14 97.79,27.95 98.83,27.95 K8.S1
  Top 2.54: X35.1 93.98,17.79
N$327
  Top 2.54: X35.4 91.44,27.6 K8.S2
N$405  (via drill 0.5)
  Top 0.229: IC1.21 165.74,70.81 165.1,70.18 151.76,70.18 151.13,70.81 IC3.1
  Top 0.254: 165.74,70.81 v165.74,73.29 | v179.96,70.37 180.59,69.74 182.66,69.74
  Top 0.305: 182.66,69.74 182.71,69.74 RN19.5
  Bottom 0.229: v165.74,73.29 165.74,73.04 166.37,73.67 179.32,73.67 179.96,73.04 v179.96,70.37
N$406  (via drill 0.5)
  Top 0.229: IC1.25 v170.81,69.99 170.81,68.28 170.18,67.64 146.69,67.64 146.05,68.28 IC3.5 | v176.53,66.37 180.02,66.37 180.34,66.05 182.64,66.05 RN18.5
  Bottom 0.229: v170.81,69.99 170.81,71.28 171.17,71.64 176.13,71.64 176.54,71.24 v176.53,66.37
N$407  (via drill 0.5)
  Top 0.229: IC1.26 v172.08,69.99 172.08,67.96 171.13,67.01 145.42,67.01 144.78,67.64 IC3.6 | v177.48,65.42 180.02,65.42 180.34,65.1 182.63,65.1 RN18.6
  Bottom 0.229: v172.08,69.99 172.08,71.01 172.21,71.13 175.39,71.13 175.51,71.01 175.51,65.67 175.77,65.42 v177.48,65.42
N$408  (via drill 0.6)
  Top 0.305: IC2.16 v59.05,74.94 | v159.38,73.67 IC1.16 | RN17.6 186.92,82.16 | 186.92,82.16 187.32,82.56 187.32,89.55 186.69,90.18 U$13.A1 | 186.92,82.16 187.09,82.16 187.32,81.93 200.02,81.93 200.66,81.29 v200.66,74.31
  Bottom 0.305: v59.05,74.94 60.33,76.21 67.95,76.21 68.58,76.85 129.54,76.85 130.18,76.21 156.21,76.21 158.75,73.67 v159.38,73.67 160.02,74.31 v200.66,74.31
N$409  (via drill 0.5)
  Top 0.229: IC1.22 167,70.18 166.37,69.54 150.5,69.54 149.86,70.18 IC3.2
  Top 0.254: 167,70.18 v167,69.99 | v178.94,69.61 179.45,69.61 180.09,68.97 182.7,68.97 RN19.6
  Bottom 0.229: v167,69.99 167,72.78 167.39,73.16 178.44,73.16 178.94,72.66 v178.94,69.61
N$410  (via drill 0.5)
  Top 0.229: IC1.23 168.27,69.54 167.64,68.91 149.23,68.91 148.59,69.54 IC3.3
  Top 0.254: 168.27,69.54 v168.27,69.99 | v178.05,68.59 178.69,68.59 179.07,68.21 182.7,68.21 RN19.7
  Bottom 0.229: v168.27,69.99 168.27,72.4 168.53,72.66 177.67,72.66 178.05,72.28 v178.05,68.59
  Bottom 0.254: 178.31,68.47 v178.05,68.59
N$411  (via drill 0.5)
  Top 0.229: IC1.24 169.55,68.91 168.91,68.28 147.95,68.28 147.32,68.91 IC3.4
  Top 0.254: 169.55,68.91 v169.55,69.99 | v177.67,67.32 182.64,67.32 RN19.8
  Bottom 0.229: v169.55,69.99 169.55,71.64 170.05,72.15 176.4,72.15 177.17,71.39 177.17,67.83 v177.67,67.32
N$416  (via drill 0.6)
  Top 0.203: 149.86,79.39 150.18,79.7 155.89,79.7 156.84,80.66 156.84,82.88 157.48,83.51 173.99,83.51 174.62,84.15 v174.62,88.91
  Top 0.229: v174.62,88.91 174.62,89.8 173.86,90.56 173.86,91.34 RN21.8
  Top 0.406: v174.62,82.56 IC1.1 | IC4.8 149.86,79.39
  Bottom 0.406: v174.62,88.91 v174.62,82.56
N$417  (via drill 0.6)
  Top 0.203: IC4.7 148.59,79.7 149.1,80.21 155.38,80.21 156.21,81.04 156.21,83.51 156.84,84.15 172.72,84.15 173.36,84.78 v173.36,88.91
  Top 0.229: v173.36,88.91 173.36,89.93 172.97,90.31 172.97,91.4 RN21.7
  Top 0.406: v173.36,82.56 IC1.2
  Bottom 0.406: v173.36,88.91 v173.36,82.56
N$418  (via drill 0.6)
  Top 0.203: IC4.6 147.32,80.02 148.02,80.72 154.62,80.72 155.57,81.67 155.57,84.15 156.21,84.78 171.45,84.78 172.08,85.42 v172.08,88.91
  Top 0.229: v172.08,88.91 172.08,90.44 172.21,90.56 172.21,91.4 RN21.6
  Top 0.406: v172.08,82.56 IC1.3
  Bottom 0.406: v172.08,88.91 v172.08,82.56
N$419  (via drill 0.6)
  Top 0.203: IC4.5 146.05,80.02 147.26,81.23 153.99,81.23 154.94,82.18 154.94,84.78 155.57,85.42 170.18,85.42 170.81,86.06 v170.81,88.91
  Top 0.229: v170.81,88.91 170.81,90.06 171.32,90.56 171.32,91.34 RN21.5
  Top 0.406: v170.81,82.56 IC1.4
  Bottom 0.406: v170.81,82.56 v170.81,88.91
N$420  (via drill 0.6)
  Top 0.203: IC4.4 144.78,80.02 146.5,81.74 153.48,81.74 154.31,82.56 154.31,85.42 154.94,86.06 168.91,86.06 169.55,86.69 v169.55,88.91
  Top 0.229: v169.55,88.91 169.55,89.67 168.91,90.31 168.91,91.34 RN20.8
  Top 0.406: v169.55,82.56 IC1.5
  Bottom 0.406: v169.55,88.91 v169.55,82.56
N$421  (via drill 0.6)
  Top 0.203: IC4.3 143.51,80.02 145.73,82.25 152.97,82.25 153.67,82.94 153.67,86.06 154.31,86.69 167.64,86.69 168.27,87.32 v168.27,88.91
  Top 0.229: v168.27,88.91 168.27,90.06 168.02,90.31 168.02,91.4 RN20.7
  Top 0.406: v168.27,82.56 IC1.6
  Bottom 0.406: v168.27,88.91 v168.27,82.56
N$422  (via drill 0.6)
  Top 0.203: IC4.2 142.24,80.02 144.97,82.75 152.34,82.75 153.03,83.45 153.03,86.69 153.67,87.32 166.56,87.32 167,87.77 v167,88.91
  Top 0.229: IC1.7 167,80.66 | v167,88.91 167,89.93 167.26,90.18 167.26,91.4 RN20.6
  Top 0.406: 167,88.54 v167,88.91 | v167,82.56 IC1.7
  Bottom 0.406: v167,88.91 v167,82.56
N$423  (via drill 0.6)
  Top 0.203: IC4.1 140.97,80.02 144.33,83.39 151.83,83.39 152.4,83.96 152.4,87.25 153.11,87.96 165.29,87.96 165.74,88.41 v165.74,88.91
  Top 0.229: v165.74,88.91 165.74,89.93 166.37,90.56 166.37,91.34 RN20.5
  Top 0.406: v165.74,82.56 IC1.8
  Bottom 0.406: v165.74,82.56 v165.74,88.91
N$424  (via drill 0.5)
  Top 0.229: IC2.21 v65.4,73.23 65.4,70.76 65.02,70.37 55.88,70.37 55.24,71.01 IC5.1 | v80.64,67.32 82.31,67.32 RN22.5
  Bottom 0.229: v65.4,73.23 65.4,74.31 66.04,74.94 80.01,74.94 80.64,74.31 v80.64,67.32
N$425  (via drill 0.5)
  Top 0.229: IC5.2 53.98,70.5 54.61,69.86 66.67,69.86 v66.67,70.05 IC2.22 | RN22.6 79.46,66.45 v79.37,66.37
  Bottom 0.229: v79.37,66.37 79.37,73.67 78.74,74.31 67.31,74.31 66.67,73.67 v66.67,70.05
N$426  (via drill 0.5)
  Top 0.229: IC5.3 52.7,69.86 53.34,69.23 67.44,69.23 67.95,69.74 v67.95,70.05 IC2.23 | RN22.7 80.24,65.65 80.01,65.42 v78.11,65.42
  Bottom 0.229: v78.11,65.42 78.11,73.04 77.47,73.67 68.58,73.67 67.95,73.04 v67.95,70.05
N$427  (via drill 0.5)
  Top 0.229: IC5.4 51.43,69.23 52.07,68.59 68.58,68.59 69.21,69.23 v69.21,70.05 IC2.24 | RN22.8 80.4,64.85 80.01,64.47 77.15,64.47 v76.52,65.1
  Bottom 0.229: v76.52,65.1 76.52,72.33 75.81,73.04 69.85,73.04 69.21,72.4 v69.21,70.05
N$428  (via drill 0.5)
  Top 0.229: IC5.5 50.17,68.59 50.8,67.96 69.85,67.96 70.48,68.59 v70.48,70.05 IC2.25 | RN23.5 80.4,63.44 v80.33,63.51
  Bottom 0.229: v80.33,63.51 76.52,63.51 75.56,64.47 75.56,71.77 74.93,72.4 71.12,72.4 70.48,71.77 v70.48,70.05
N$429  (via drill 0.5)
  Top 0.229: IC5.6 48.89,67.96 49.53,67.32 71.12,67.32 71.76,67.96 v71.76,70.05 IC2.26 | RN23.6 79.46,62.64 v79.37,62.56
  Bottom 0.229: v79.37,62.56 76.2,62.56 74.61,64.15 74.61,71.06 73.9,71.77 72.09,71.77 IC2.26 v71.76,70.05
N$430  (via drill 0.5)
  Top 0.229: IC5.7 47.62,67.32 48.26,66.69 72.39,66.69 73.02,67.32 v73.02,70.05 IC2.27 | RN23.7 80.24,61.84 80.01,61.61 v78.11,61.61
  Bottom 0.229: v78.11,61.61 74.93,61.61 73.02,63.51 v73.02,70.05
N$431
  Top 0.229: IC2.28 74.3,66.69 | 74.3,66.69 73.66,66.05 46.99,66.05 46.35,66.69 IC5.8 | RN23.8 79.13,61.04 78.74,60.65 77.15,60.65 76.83,60.97 76.83,63.51 74.3,66.05 74.3,66.69
N$441
  Top 0.406: RN5.1 121.36,83.76 120.65,84.47 94.5,84.47 R16.C
N$442
  Top 0.406: RN8.7 RN7.2
N$443
  Top 0.406: RN7.3 RN8.6
N$444
  Top 0.406: RN8.5 RN7.4
N$445
  Top 0.406: RN5.2 120.89,82.96 120.02,83.83 97.67,83.83 R15.C
N$446
  Top 0.406: RN4.3 28.34,78.35 26.03,80.66 22.74,80.66 R22.C
N$447
  Top 0.406: RN5.4 119.95,81.36 118.74,82.56 104.02,82.56 R13.C
N$448
  Top 0.406: RN5.5 RN6.4
N$449
  Top 0.406: RN7.1 RN8.8
N$450
  Top 0.406: RN8.1 120.08,79.95 118.11,81.93 107.2,81.93 R12.C
N$451
  Top 0.406: RN5.6 RN6.3
N$452
  Top 0.406: RN8.2 119.61,79.15 117.48,81.29 110.37,81.29 R11.C
N$453
  Top 0.406: RN6.2 RN5.7
N$454
  Top 0.406: RN5.8 RN6.1
N$455
  Top 0.406: RN3.4 RN4.5
N$458
  Top 0.406: RN5.3 120.42,82.16 119.38,83.2 100.85,83.2 R14.C
N$459
  Top 0.406: RN8.3 119.14,78.35 116.84,80.66 113.55,80.66 R10.C
N$461
  Top 0.406: RN4.1 29.28,79.95 27.3,81.93 16.39,81.93 R24.C
N$462
  Top 0.406: RN4.2 28.81,79.15 26.67,81.29 19.57,81.29 R23.C
N$463
  Top 0.406: RN12.4 RN11.5
N$464
  Top 0.305: R21.C 25.52,79.39
  Top 0.406: RN4.4 27.87,77.55 26.03,79.39 25.52,79.39
N$470
  Top 0.406: RN8.4 118.67,77.55 116.84,79.39 116.32,79.39 R9.C
N$473
  Top 0.406: RN12.5 118.67,74.87 116.84,73.04 116.32,73.04 R1.C
N$474
  Top 0.406: RN11.6 RN12.3
N$475
  Top 0.406: RN12.6 119.14,74.07 116.84,71.77 113.55,71.77 R2.C
N$476
  Top 0.406: RN12.7 119.61,73.27 117.48,71.13 110.37,71.13 R3.C
N$477
  Top 0.406: RN9.4 RN10.5
N$478
  Top 0.406: RN10.6 RN9.3
N$479
  Top 0.406: RN9.2 RN10.7
N$480
  Top 0.406: RN10.8 RN9.1
N$481
  Top 0.406: RN12.2 RN11.7
N$482
  Top 0.406: RN10.1 119.95,71.06 118.74,69.86 104.02,69.86 R5.C
N$483
  Top 0.406: RN12.8 120.08,72.47 118.11,70.5 107.2,70.5 R4.C
N$484
  Top 0.406: RN10.3 120.89,69.46 120.02,68.59 97.67,68.59 R7.C
N$485
  Top 0.406: RN10.4 121.36,68.66 120.65,67.96 94.5,67.96 R8.C
N$486
  Top 0.406: RN10.2 120.42,70.26 119.38,69.23 100.85,69.23 R6.C
N$487
  Top 0.406: RN14.3 29.44,73.27 27.3,71.13 19.57,71.13 R19.C
N$488
  Top 0.406: RN14.2 28.97,74.07 26.67,71.77 22.74,71.77 R18.C
N$489
  Top 0.406: RN14.1 28.5,74.87 26.67,73.04 25.52,73.04 R17.C
N$494
  Top 0.406: RN14.4 29.91,72.47 27.94,70.5 16.39,70.5 R20.C
N$498  (via drill 0.6)
  Top 0.305: IC2.17 v60.33,73.67 | v156.21,73.67 156.21,74.94 156.84,75.58 v159.38,75.58 160.02,75.58 160.65,74.94 IC1.17 | U$13.B1 183.51,86.37 183.51,81.29 183.58,81.36 RN17.5 198.37,81.36 199.07,80.66 v199.07,75.58
  Bottom 0.305: v60.33,73.67 62.23,75.58 68.58,75.58 69.21,76.21 128.97,76.21 129.54,75.58 155.57,75.58 156.21,74.94 v156.21,73.67 | v159.38,75.58 v199.07,75.58
N$500
  Top 0.406: RN11.8 RN12.1
N$501
  Top 0.406: RN13.4 RN14.5
N$502
  Top 0.406: RN14.6 RN13.3
N$503
  Top 0.406: RN13.2 RN14.7
N$504
  Top 0.406: RN14.8 RN13.1
N$505
  Top 0.406: RN4.6 RN3.3
N$506
  Top 0.406: RN4.7 RN3.2
N$507
  Top 0.406: RN4.8 RN3.1
N$515
  Top 0.254: POWER.A 215.15,74.42 213.68,75.89 211.7,75.89 RNB.3
  Top 0.305: RNB.3 211.56,76.02
N$516
  Top 0.254: RNB.4 212.4,76.84 213.68,78.12 215.78,78.12 I2C.A
  Top 0.305: RNB.4
N$517  (via drill 0.6)
  Top 0.254: RNE.5 230.61,81.78 v230.63,81.8
  Bottom 0.254: v230.63,81.8 225.04,81.8 224.92,81.93 203.83,81.93 202.56,83.2 202.56,89.87 202.25,90.18 U$16.A1
N$518  (via drill 0.6)
  Top 0.254: RNE.6 227.73,81.37 227.33,80.98 v224.79,80.98
  Bottom 0.254: U$16.B1 200.66,87.64 201.29,87.01 201.29,81.93 202.56,80.66 225.11,80.66 v224.79,80.98
N$524
  Bottom 2.54: 229.87,62.24 229.23,62.24
N$525  (via drill 0.5)
  Top 0.229: IC3.7 143.51,67.01 144.14,66.37 172.4,66.37 173.36,67.32 v173.36,69.99 IC1.27 | v178.44,64.47 182.16,64.47 RN18.7
  Bottom 0.229: v178.44,64.47 173.67,64.47 173.36,64.78 v173.36,69.99
N$526
  Top 0.229: IC1.28 174.62,66.37 | 174.62,66.37 173.99,65.73 142.88,65.73 142.24,66.37 IC3.8 | 174.62,66.37 174.62,64.15 175.26,63.51 182.64,63.51 RN18.8
OC_R1_A  (via drill 0.6)
  Top 0.406: IC3.18 v151.13,62.31 152.46,60.97 208.28,60.97 208.91,60.34 208.91,57.16 209.55,56.53 222.25,56.53 222.88,55.89 K1.2 | RN11.4 139,74.87 v139.19,74.69
  Bottom 0.406: v139.19,74.69 150.5,74.69 151.13,74.05 v151.13,62.31
OC_R1_B
  Top 0.203: RN7.5 137.87,77.55 144.46,84.15 148.91,84.15 149.86,85.1 IC4.11
  Top 0.406: IC4.11 149.86,92.72 150.5,93.36 161.29,93.36 161.93,93.99 194.31,93.99 195.58,95.26 222.25,95.26 222.88,95.9 K9.2
OC_R1_C  (via drill 0.6)
  Top 0.406: v43.18,74.94 43.11,74.87 RN13.8 | IC5.18 v55.24,62.24 55.24,60.34 56.52,59.07 66.04,59.07 66.67,58.43 K17.2
  Bottom 0.406: v43.18,74.94 53.98,74.94 55.24,73.67 v55.24,62.24
OC_R2_A  (via drill 0.6)
  Top 0.406: RN11.3 137.39,74.07 v137.8,73.67 | IC3.17 v149.86,62.31 149.9,60.37 150.59,59.7 207.01,59.7 207.64,59.07 K2.2
  Bottom 0.406: v137.8,73.67 148.59,73.67 149.86,72.4 v149.86,62.31
OC_R2_B
  Top 0.203: IC4.12 148.59,85.74 147.64,84.78 144.46,84.78 138.03,78.35 RN7.6
  Top 0.406: IC4.12 148.59,93.36 149.23,93.99 160.65,93.99 161.29,94.63 193.67,94.63 194.94,95.9 207.01,95.9 207.64,96.53 K10.2
OC_R2_C  (via drill 0.6)
  Top 0.406: RN13.7 41.51,74.07 v41.91,73.67 | IC5.17 v53.98,62.24 53.98,57.8 51.43,55.26 K18.2
  Bottom 0.406: v41.91,73.67 51.43,73.67 53.98,71.13 v53.98,62.24
OC_R3_A  (via drill 0.6)
  Top 0.406: RN11.2 135.65,73.27 v136.52,72.4 | IC3.16 v148.59,62.31 148.59,59.07 149.23,58.43 191.77,58.43 192.4,57.8 K3.2
  Bottom 0.406: v136.52,72.4 147.32,72.4 148.59,71.13 v148.59,62.31
OC_R3_B
  Top 0.203: RN7.7 138.19,79.15 144.46,85.42 147,85.42 147.32,85.74 IC4.13
  Top 0.406: IC4.13 147.32,93.99 147.95,94.63 160.02,94.63 160.65,95.26 191.77,95.26 192.4,95.9 K11.2
OC_R3_C  (via drill 0.6)
  Top 0.406: RN13.6 39.77,73.27 v40.64,72.4 | IC5.16 v52.7,62.24 52.7,57.8 51.43,56.53 36.83,56.53 36.19,55.89 K19.2
  Bottom 0.406: v40.64,72.4 50.17,72.4 52.7,69.86 v52.7,62.24
OC_R4_A  (via drill 0.6)
  Top 0.406: RN11.1 133.92,72.47 v135.25,71.13 | IC3.15 v147.32,62.31 147.32,57.8 147.95,57.16 176.53,57.16 177.17,56.53 K4.2
  Bottom 0.406: v135.25,71.13 146.05,71.13 147.32,69.86 v147.32,62.31
OC_R4_B
  Top 0.203: RN7.8 138.36,79.95 144.46,86.06 145.73,86.06 146.05,86.37 IC4.14
  Top 0.406: IC4.14 146.05,94.63 146.69,95.26 159.38,95.26 160.08,95.96 176.21,95.96 177.17,96.91 K12.2
OC_R4_C  (via drill 0.6)
  Top 0.406: RN13.5 38.03,72.47 v39.37,71.13 | IC5.15 v51.43,62.24 51.43,58.43 50.8,57.8 24.13,57.8 20.95,54.62 K20.2
  Bottom 0.406: v39.37,71.13 48.89,71.13 51.43,68.59 v51.43,62.24
OC_R5_A  (via drill 0.6)
  Top 0.406: RN9.8 132.78,71.06 133.99,69.86 v139.06,69.86 | IC3.14 v146.05,62.31 146.05,56.53 144.78,55.26 K5.2
  Bottom 0.406: v139.06,69.86 144.78,69.86 146.05,68.59 v146.05,62.31
OC_R5_B
  Top 0.203: IC4.15 144.78,87.01 144.46,86.69 144.14,86.69 138.82,81.36 RN6.5
  Top 0.406: K13.2 IC4.15
OC_R5_C  (via drill 0.5, 0.6)
  Top 0.406: v50.17,62.24 IC5.14 | v41.91,76.85 41.27,77.48 36.43,77.48 RN3.5
  Top 0.61: K25.2 v66.67,92.72
  Bottom 0.406: v50.17,62.24 50.17,67.96 48.26,69.86 39,69.86 38.1,70.76 38.1,76.21 38.73,76.85 v41.91,76.85
  Bottom 0.61: v66.67,92.72 53.98,92.72 53.34,92.09 53.34,78.75 51.43,76.85 v41.91,76.85
OC_R6_A  (via drill 0.6)
  Top 0.406: RN9.7 132.31,70.26 133.99,68.59 v137.8,68.59 | IC3.13 v144.78,62.31 144.78,58.43 143.51,57.16 130.18,57.16 129.54,56.53 K6.2
  Bottom 0.406: v137.8,68.59 143.51,68.59 144.78,67.32 v144.78,62.31
OC_R6_B
  Top 0.203: RN6.6 138.67,82.16 143.51,87.01 IC4.16
  Top 0.406: IC4.16 143.51,95 142.61,95.9 130.44,95.9 129.54,96.8 K14.2
OC_R6_C  (via drill 0.5, 0.6)
  Top 0.406: v48.89,62.24 IC5.13 | v42.55,78.12 38.1,78.12 37.21,78.37 36.38,78.37 RN3.6
  Top 0.61: K26.2 v51.43,92.72
  Bottom 0.406: v48.89,62.24 48.89,67.32 47.62,68.59 39.37,68.59 37.46,70.5 37.46,76.85 38.73,78.12 v42.55,78.12
  Bottom 0.61: v51.43,92.72 51.43,79.39 50.17,78.12 v42.55,78.12
OC_R7_A  (via drill 0.6)
  Top 0.406: RN9.6 131.84,69.46 133.99,67.32 v136.52,67.32 | IC3.12 v143.51,62.31 143.51,59.7 142.24,58.43 114.93,58.43 114.3,57.8 K7.2
  Bottom 0.406: v136.52,67.32 142.24,67.32 143.51,66.05 v143.51,62.31
OC_R7_B
  Top 0.203: 138.51,82.96 142.24,86.69 IC4.17
  Top 0.229: 138.51,82.96 RN6.7
  Top 0.406: IC4.17 142.24,93.36 141.61,93.99 114.93,93.99 114.3,94.63 K15.2
OC_R7_C  (via drill 0.5, 0.6)
  Top 0.406: v47.62,62.24 IC5.12 | v41.91,79.39 41.66,79.13 36.38,79.13 RN3.7
  Top 0.61: K27.2 v36.19,92.72
  Bottom 0.406: v47.62,62.24 47.62,66.05 46.35,67.32 38.73,67.32 36.83,69.23 36.83,78.12 38.1,79.39 v41.91,79.39
  Bottom 0.61: v41.91,79.39 41.91,87.01 v36.19,92.72
OC_R8_A  (via drill 0.6)
  Top 0.406: RN9.5 131.38,68.66 133.99,66.05 v135.25,66.05 | IC3.11 v142.24,62.31 142.24,60.97 140.97,59.7 100.33,59.7 99.06,58.43 K8.2
  Bottom 0.406: v135.25,66.05 140.97,66.05 142.24,64.78 v142.24,62.31
OC_R8_B
  Top 0.203: 138.36,83.76 140.97,86.37 IC4.18
  Top 0.229: 138.36,83.76 RN6.8
  Top 0.406: IC4.18 140.97,92.09 140.33,92.72 99.7,92.72 99.06,93.36 K16.2
OC_R8_C  (via drill 0.5, 0.6)
  Top 0.406: v46.35,62.24 IC5.11 | RN3.8 36.43,80.02 37.46,80.02 38.1,80.66 v40,80.66
  Top 0.61: K28.2 v20.95,92.72
  Bottom 0.406: v46.35,62.24 46.35,64.78 45.08,66.05 38.73,66.05 36.19,68.59 36.19,78.75 38.1,80.66 v40,80.66
  Bottom 0.61: v20.95,92.72 33.66,92.72 40,86.37 v40,80.66
REG_5V  (via drill 0.5, 0.6)
  Top 0.254: RNB.6 209.38,76.04 208.91,75.58 208.91,72.72 209.23,72.4 CB2.2 | 193.36,88.28 193.36,91.14 193.04,91.45 182.88,91.45 182.25,90.82 182.25,90.5 U$13.A2
  Top 0.305: IC2.15 v57.78,77.48 58.42,77.48 61.59,74.31 61.59,71.13 | 161.93,77.48 163.19,78.75 163.83,78.75 164.46,79.39 | IC2.9 64.14,80.02 v62.86,78.75 | IC1.18 v161.93,76.85 | IC1.9 164.46,79.39 | 164.46,79.39 165.1,78.75 175.58,78.75 175.89,78.75 177.17,80.02 177.8,80.02 | 177.8,80.02 182.25,80.02 182.33,79.93 C1.1 | 177.8,80.02 180.97,83.2 182.25,83.2 182.48,82.96 RN17.2 RN17.1 182.71,87.17 U$13.B2 U$13.A2
  Top 0.406: C2.1 C3.1 81.92,71.22 81.92,69.54 | C4.1 C1.1 | IC2.18 61.59,74.31 62.23,74.94 76.61,74.94 | C8.1 76.61,74.94 | 76.61,74.94 C5.1 | C6.1 C7.1 176.94,77.71 175.89,78.75
  Top 0.813: CB2.2 CA2.2 204.7,70.73 203.83,69.86 | 203.83,69.86 IC7.1 | 203.83,69.86 203.83,71.13 203.07,71.89 202.44,71.89 201.93,72.4 201.93,84.47 200.66,85.74 196.09,85.74 195.2,86.63 195.2,87.58 U$16.B2 | 81.92,69.54 82.23,69.23 85.09,69.23 C18.+ | C3.1 81.68,69.63 81.28,69.23 77.09,69.23 76.58,69.74 76.58,71.43 C5.1 | C2.1 81.68,83.6 C19.+
  Top 1.27: 194.94,87.32 U$16.B2 | U$16.B2 193.99,87.64 193.36,88.28 193.36,91.77 193.04,92.09 183.83,92.09 182.25,90.5 U$13.B2 182.25,83.51 180.66,83.51 177.48,80.34 177.17,80.34 175.58,78.75 164.78,78.75 164.46,79.07 163.51,79.07 161.93,77.48 v161.93,76.85 | C17.+ v193.67,80.02 | v193.67,83.2 193.67,86.06 U$16.B2
  Bottom 0.305: v161.93,76.85 130.81,76.85 130.18,77.48 67.95,77.48 67.31,76.85 66.04,76.85 65.4,77.48 v57.78,77.48 57.78,78.12 58.42,78.75 v62.86,78.75
  Bottom 0.813: U$16.B2 U$16.A2
  Bottom 1.27: v193.67,80.02 v193.67,83.2
REG_5V_BUS
  Top 0.254: 231.14,72.72 224.47,72.72 224.15,73.04 224.15,78.75 223.84,79.07 210.82,79.07 210.19,78.43 210.19,77.07
  Top 0.305: 210.19,77.07 RNB.5
  Top 0.61: X25.3 231.14,72.72 | X27.2 231.52,89.48
  Bottom 0.406: 231.52,89.48 X27.2 | 231.14,72.72 X25.3
  Bottom 0.813: 231.14,72.72 233.04,72.72 234.31,73.99 234.31,87.32 232.03,89.48 231.52,89.48
REG_12V
  Top 0.813: CB1.2 CA1.2 204.7,62.65 203.83,63.51 IC7.8
  Top 1.016: C20.+ 213.36,62.56
  Top 1.27: BRA1.+ 222.57,63.01 222.12,62.56 213.36,62.56 209.32,62.56 CB1.2
UNREG_12V  (via drill 0.6)
  Top 0.305: 116.2,76.21 R1.A
  Top 0.406: IC5.10 v45.08,62.24 | IC4.10 v151.13,86.06 | R8.A 89.53,76.21 | R15.A 93.34,76.21 | R6.A 97.15,76.21 | 100.96,76.21 R13.A | R4.A 104.77,76.21 | R3.A 108.58,76.21 | R2.A 112.39,76.21 | R16.A 89.53,76.21 | 89.53,76.21 93.34,76.21 | R7.A 93.34,76.21 | 93.34,76.21 97.15,76.21 | R14.A 97.15,76.21 | 97.15,76.21 100.96,76.21 | R5.A 100.96,76.21 | 100.96,76.21 104.77,76.21 | R12.A 104.77,76.21 | 104.77,76.21 108.58,76.21 | R11.A 108.58,76.21 | 108.58,76.21 112.39,76.21 | R10.A 112.39,76.21 | R24.A 13.97,76.21 | v17.78,76.21 R19.A | 21.59,76.21 R18.A | R21.A 25.4,76.21 | 25.4,76.21 R17.A | R20.A 13.97,76.21 | 13.97,76.21 v17.78,76.21 | v17.78,76.21 21.59,76.21 | R22.A 21.59,76.21 | 21.59,76.21 25.4,76.21 | R9.A 116.2,76.21 | 116.2,74.31 116.2,76.21 | 116.2,76.21 113.98,76.21 | 112.39,76.21 113.98,76.21 | 113.98,76.21 v113.98,73.04 | IC3.10 140.97,62.88 v140.93,62.31 | R23.A v17.78,76.21
  Top 1.27: U$14.TIP 228.82,62.46 225.42,59.07 BRA1.~@1 BRA1.~@2
  Bottom 0.406: v151.13,86.06 151.13,94.63 150.5,95.26 | v113.98,73.04 113.98,57.16 107.44,57.16 106.81,56.53 | 125.79,57.48 126.11,57.16 | v17.78,76.21 17.78,57.16 | 36.19,57.16 28.83,57.16 28.7,57.04
  Bottom 0.813: v45.08,62.24 45.08,57.16
  Bottom 1.016: 125.79,57.48 140.93,57.48 v140.93,62.31 | C23.+ 77.47,57.16 | C24.+ 85.09,95.26
  Bottom 1.422: C22.+ 85.73,95.26 | C21.+ 36.19,57.16
  Bottom 2.54: 229.23,57.16 228.85,56.78 228.85,53.35 229.19,53.01 X26.2 | 229.23,57.16 215.26,57.16 | 215.26,57.16 200.02,57.16 | 200.02,57.16 184.78,57.16 | 184.78,57.16 169.55,57.16 | 169.55,57.16 136.52,57.16 | 136.52,57.16 126.11,57.16 121.92,57.16 | 121.92,57.16 113.98,57.16 91.44,57.16 | 91.44,57.16 77.47,57.16 59.05,57.16 | 59.05,57.16 47.62,57.16 | 47.62,57.16 45.08,57.16 36.19,57.16 28.58,57.16 | 28.58,57.16 17.78,57.16 13.33,57.16 | 13.33,57.16 12.7,57.16 12.7,95.26 28.58,95.26 | 28.58,95.26 59.05,95.26 | 59.05,95.26 85.09,95.26 85.73,95.26 | 85.73,95.26 89.53,95.26 | 89.53,95.26 121.92,95.26 | 121.92,95.26 137.16,95.26 | 137.16,95.26 150.5,95.26 152.4,95.26 | 152.4,95.26 167.64,95.26 | 167.64,95.26 184.78,95.26 | 184.78,95.26 200.02,95.26 | 200.02,95.26 215.26,95.26 | 215.26,95.26 229.87,95.26 230.5,95.9 230.5,99.58 K9.1 | 228.62,56.82 229.23,57.16 | 229.23,57.16 229.23,62.22 U$14.TIP | K28.1 28.45,95.39 28.58,95.26 | K27.1 43.69,95.39 85.73,95.26 | K26.1 58.93,95.39 59.05,95.26 | K25.1 74.17,95.39 89.53,95.26 | K20.1 13.46,57.04 13.33,57.16 | K19.1 28.7,57.04 28.58,57.16 | K18.1 43.94,57.04 47.62,57.16 | K17.1 59.18,57.04 59.05,57.16 | K8.1 91.57,57.04 91.44,57.16 | K7.1 106.81,56.53 106.81,57.04 106.68,57.16 | K6.1 122.05,57.04 121.92,57.16 | K5.1 137.29,56.4 136.52,57.16 | K4.1 169.67,57.04 169.55,57.16 | K3.1 184.91,57.04 184.78,57.16 | K2.1 200.15,57.04 200.02,57.16 | K1.1 215.39,57.04 215.26,57.16 | K16.1 106.55,95.39 121.92,95.26 | K15.1 121.79,95.39 137.16,95.26 | K14.1 137.03,95.39 152.4,95.26 | K13.1 152.27,95.39 167.64,95.26 | K12.1 184.66,95.39 184.78,95.26 | K11.1 199.9,95.39 200.02,95.26 | K10.1 215.14,95.39 215.26,95.26

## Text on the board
tNames: 5 | 8 | 5 | 4 | 1 | 8 | Bank 2 | Bank 3 | I2CIO8R24xDPDT | MCP23017 | GPB0 | REV.E | GND | GPB1 | I2C 5V | Address: | PULL-UP | GND | GPB2 | +5V | A1 | SDA | A2 | GND | SCL | I2C OUT | GPB3 | SCL | GPB4 | SDA | +5V | GND | I2C IN | GND | GPB5 | Address A0=0 | Address A0=1 | GPB6 | GND | GPB7 | 12V DC / Power / Supply | 2016 ControlEverything.com | Bank 3 | Bank 1 | 4 | 1 | 8 | 5 | 4 | 1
